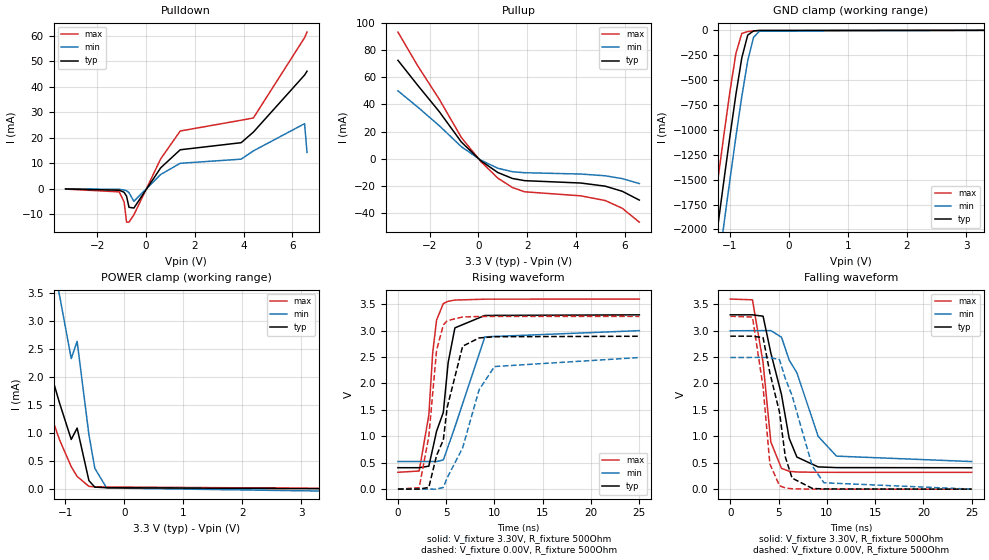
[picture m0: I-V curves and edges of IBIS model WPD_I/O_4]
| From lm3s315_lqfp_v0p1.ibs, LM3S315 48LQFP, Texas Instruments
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[Model]   WPD_I/O_4
Model_type   I/O
Vinl = 1.26
Vinh = 2.04
Vmeas = 1.65
| variable   typ   min   max
C_comp   9.739pF   9.739pF   9.739pF
[Model Spec]
Vinh+   1.91   1.78   2.04
Vinh-   1.90   1.76   2.03
Vinl+   1.40   1.27   1.54
Vinl-   1.39   1.26   1.53
| variable   typ   min   max
[Temperature Range]  25   85   -40
[Voltage Range]   3.3V   3.0V   3.6V
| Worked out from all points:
|   slope of the pulldown table from 0 to 0.495 V, typ, clamps not added: 71.6 ohm
|   slope of the pullup table from 0 to 0.495 V, typ, clamps not added: 71.6 ohm
|   GND clamp passes 1 mA (typ) near -0.48 V on its own axis
|   POWER clamp passes 1 mA (typ) near -0.79 V on its own axis
|   falling waveform, V_fixture 3.30V, R_fixture 500Ohm: 20-80 % time 2.05ns typ, 3.09ns min, 1.37ns max; typ from 3.3 V to 0.405 V
|   rising waveform, V_fixture 3.30V, R_fixture 500Ohm: 20-80 % time 1.61ns typ, 2.31ns min, 1.11ns max; typ from 0.405 V to 3.3 V
|   falling waveform, V_fixture 0.00V, R_fixture 500Ohm: 20-80 % time 1.77ns typ, 2.51ns min, 1.22ns max; typ from 2.89 V to 0 V
|   rising waveform, V_fixture 0.00V, R_fixture 500Ohm: 20-80 % time 1.94ns typ, 2.99ns min, 1.25ns max; typ from 0 V to 2.89 V
[Pulldown]
|  Voltage   I(typ)   I(min)   I(max)
-3.3V     -128.2uA   -72.79uA   -182.2uA
-1.1V     -636.2uA   -293.6uA   -1.283mA
-900mV    -1.442mA   -530.2uA   -5.267mA
-800mV    -2.996mA   -834.9uA   -13.19mA
-700mV    -7.354mA   -1.607mA   -13.15mA
-500mV    -7.623mA   -4.999mA   -10.32mA
600mV     8.173mA    5.562mA    11.69mA
1.4V      15.26mA    9.946mA    22.63mA
3.9V      18.04mA    11.57mA    26.87mA
4.4V      22.2mA     14.82mA    27.75mA
6.5V      44.61mA    25.51mA    59.29mA
6.6V      46.11mA    14.23mA    61.49mA
[Pullup]
|  Voltage   I(typ)   I(min)   I(max)
-3.3V     72.49mA    49.98mA    93.27mA
-2.5V     54.33mA    38.19mA    68.75mA
-1.6V     34.53mA    24.21mA    43.65mA
-700mV    12.28mA    8.827mA    15.65mA
100mV     -1.569mA   -1.126mA   -2.147mA
800mV     -10.24mA   -7.086mA   -14.4mA
1.4V      -14.62mA   -9.643mA   -21.31mA
1.9V      -16.21mA   -10.36mA   -24.42mA
4.2V      -17.95mA   -11.33mA   -27.4mA
5.2V      -20.26mA   -12.61mA   -30.84mA
5.9V      -24.04mA   -14.71mA   -36.57mA
6.6V      -30.54mA   -18.34mA   -46.81mA
[GND Clamp]
|  Voltage   I(typ)   I(min)   I(max)
-3.3V     -11.72A    -12.12A    -11.3A
-1.4V     -2.845A    -3.285A    -2.387A
-1.3V     -2.39A     -2.831A    -1.93A
-1.2V     -1.938A    -2.38A     -1.478A
-1.1V     -1.494A    -1.934A    -1.036A
-1V       -1.059A    -1.496A    -610.6mA
-900mV    -645mA     -1.069A    -232.9mA
-800mV    -277.1mA   -664.4mA   -31.59mA
-700mV    -48.56mA   -306.6mA   -12.1mA
-600mV    -5.561mA   -70.2mA    -6.281mA
-500mV    -1.172mA   -7.88mA    -2.176mA
3.3V      16.11uA    11.84uA    29.77uA
[POWER Clamp]
|  Voltage   I(typ)   I(min)   I(max)
-3.3V     12.42mA    17.27mA    12.25mA
-1.9V     4.935mA    8.337mA    4.102mA
-1.8V     4.461mA    7.714mA    3.616mA
-1.6V     3.549mA    6.478mA    2.703mA
-1.2V     1.906mA    4.063mA    1.182mA
-1.1V     1.542mA    3.476mA    880.4uA
-900mV    882uA      2.332mA    394.1uA
-800mV    1.086mA    2.641mA    218.2uA
-600mV    142.8uA    965.1uA    40.85uA
-500mV    27.22uA    363.6uA    30.71uA
-300mV    16.12uA    11.84uA    29.79uA
3.3V      -104.7pA   -42.65uA   5.692uA
[Ramp]
| variable   typ   min   max
dV/dt_f   1.73/2.05n   1.48/3.09n   1.97/1.37n
dV/dt_r   1.74/1.94n   1.49/2.99n   1.96/1.25n
R_load = 500Ohm
[Falling Waveform]
V_fixture = 3.30V
V_fixture_min = 3.00V
V_fixture_max = 3.60V
R_fixture = 500Ohm
|   Time   V(typ)   V(min)   V(max)
0s        3.297V     2.995V     3.595V
2.3ns     3.297V     2.997V     3.581V
3.4ns     3.271V     2.998V     2.39V
4.2ns     2.577V     2.998V     893.2mV
5.3ns     1.792V     2.875V     394.2mV
6.1ns     962.2mV    2.44V      338.8mV
6.9ns     607.4mV    2.202V     324.6mV
9.1ns     421.1mV    998.9mV    318.9mV
11ns      407.9mV    624.6mV    318.6mV
25ns      405.4mV    522.4mV    318.5mV
[Rising Waveform]
V_fixture = 3.30V
V_fixture_min = 3.00V
V_fixture_max = 3.60V
R_fixture = 500Ohm
|   Time   V(typ)   V(min)   V(max)
0s        405.4mV    522.4mV    318.5mV
2.2ns     405.4mV    522.4mV    342.1mV
3.2ns     434.8mV    522.4mV    1.403V
3.6ns     761.7mV    522.3mV    2.579V
4ns       1.095V     520.9mV    3.199V
4.7ns     1.452V     551.4mV    3.512V
5.2ns     2.393V     808.8mV    3.555V
5.9ns     3.052V     1.174V     3.578V
9ns       3.287V     2.882V     3.595V
25ns      3.298V     2.999V     3.597V
[Falling Waveform]
V_fixture = 0.00V
V_fixture_min = 0.00V
V_fixture_max = 0.00V
R_fixture = 500Ohm
|   Time   V(typ)   V(min)   V(max)
0s        2.893V     2.49V      3.27V
2.3ns     2.893V     2.491V     3.255V
3.4ns     2.865V     2.491V     1.929V
4.1ns     2.201V     2.491V     478mV
5.1ns     1.455V     2.448V     64.64mV
5.7ns     611mV      2.094V     22.44mV
6.4ns     209.3mV    1.769V     7.462mV
8.5ns     13.92mV    435.2mV    569.2uV
9.7ns     4.121mV    120.7mV    206.4uV
25ns      18.45uV    33.67uV    11.46uV
[Rising Waveform]
V_fixture = 0.00V
V_fixture_min = 0.00V
V_fixture_max = 0.00V
R_fixture = 500Ohm
|   Time   V(typ)   V(min)   V(max)
0s        275.6uV    4.409mV    16.9uV
2.2ns     48.91uV    1.079mV    26.48mV
3.2ns     32.91mV    595.3uV    1V
4ns       636.7mV    -1.097mV   2.624V
4.7ns     929mV      32.28mV    3.107V
5.1ns     1.546V     213.9mV    3.188V
6.7ns     2.704V     779.6mV    3.258V
8.4ns     2.861V     1.878V     3.267V
10ns      2.884V     2.32V      3.269V
25ns      2.893V     2.49V      3.269V
